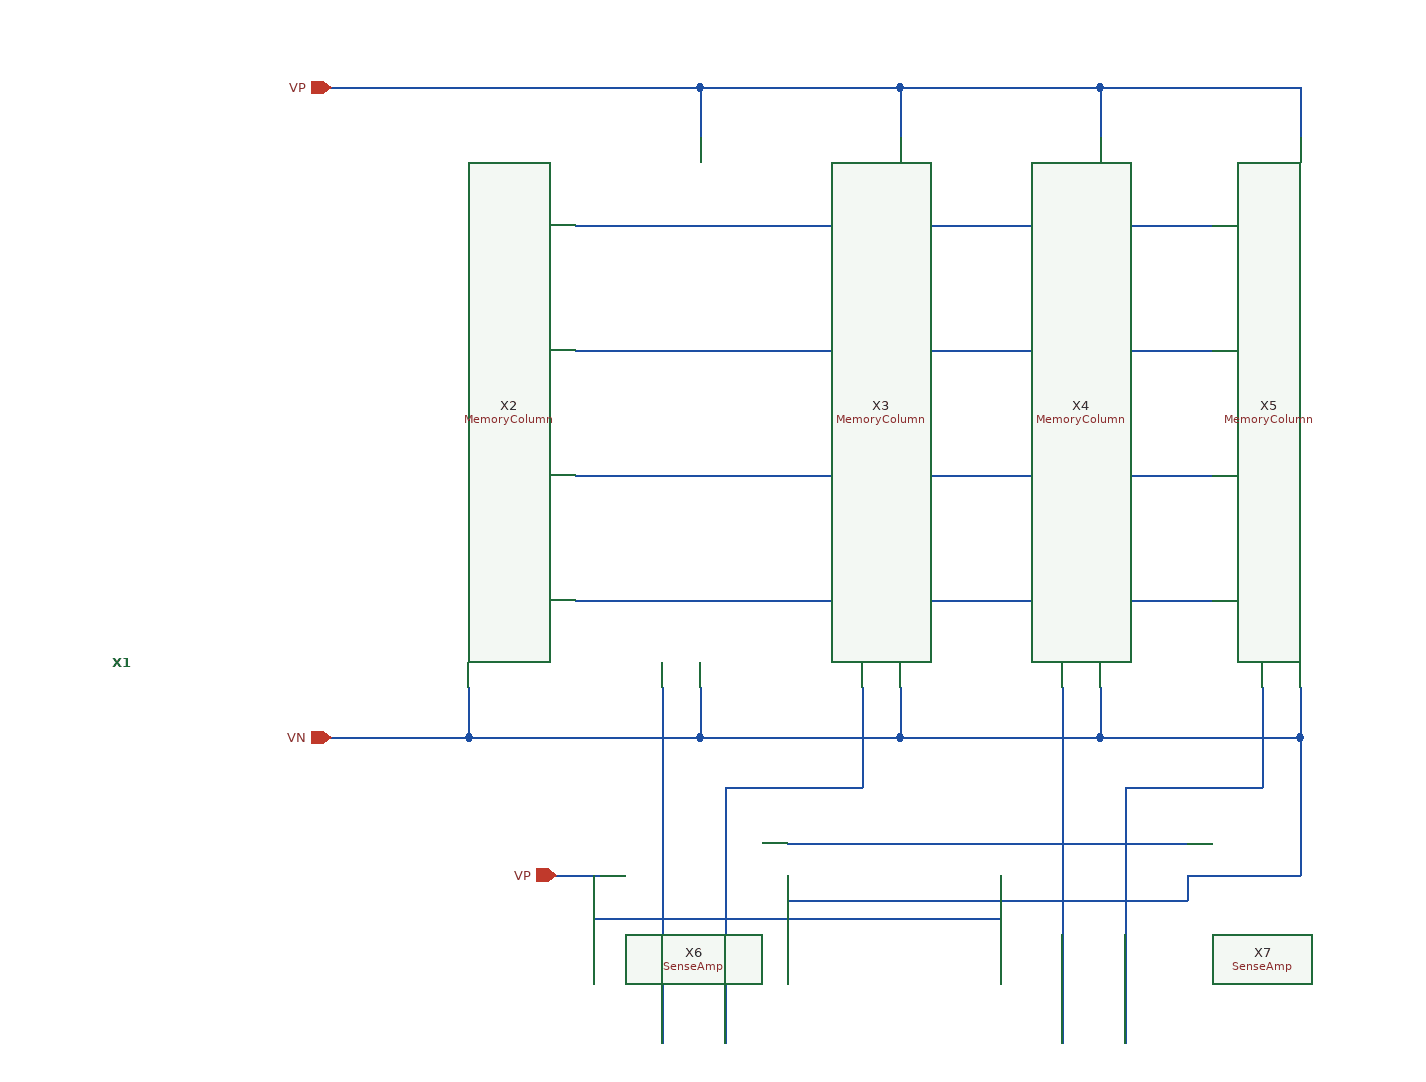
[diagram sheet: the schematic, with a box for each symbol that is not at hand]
v {xschem version=2.9.9 file_version=1.2 }
G {}
K {}
V {}
S {}
E {}
N -40 40 70 40 { lab=VN}
N 70 -0 70 40 { lab=VN}
N 70 40 255 40 { lab=VN}
N 255 -0 255 40 { lab=VN}
N 255 40 415 40 { lab=VN}
N 415 -0 415 40 { lab=VN}
N 415 40 575 40 { lab=VN}
N 575 0 575 40 { lab=VN}
N 575 40 735 40 { lab=VN}
N 735 0 735 40 { lab=VN}
N 735 -480 735 -440 { lab=VP}
N 575 -480 735 -480 { lab=VP}
N 575 -480 575 -440 { lab=VP}
N 415 -480 575 -480 { lab=VP}
N 415 -480 415 -440 { lab=VP}
N 255 -480 255 -440 { lab=VP}
N 255 -480 415 -480 { lab=VP}
N -40 -480 255 -480 { lab=VP}
N 225 -0 225 80 { lab=#net1}
N 385 0 385 80 { lab=#net2}
N 545 0 545 80 { lab=#net3}
N 705 0 705 80 { lab=#net4}
N 155 -70 665 -70 { lab=#net5}
N 155 -170 665 -170 { lab=#net6}
N 155 -270 665 -270 { lab=#net7}
N 155 -370 665 -370 { lab=#net8}
N 275 80 385 80 { lab=#net2}
N 595 80 705 80 { lab=#net4}
N 645 150 730 150 { lab=VN}
N 730 150 735 150 { lab=VN}
N 735 40 735 150 { lab=VN}
N 325 125 645 125 { lab=#net9}
N 140 150 175 150 { lab=VP}
N 645 150 645 170 { lab=VN}
N 325 170 645 170 { lab=VN}
N 325 150 325 170 { lab=VN}
N 495 150 495 185 { lab=VP}
N 170 185 495 185 { lab=VP}
N 170 150 170 185 { lab=VP}
N 225 80 225 285 { lab=#net1}
N 275 80 275 285 { lab=#net2}
N 545 80 545 285 { lab=#net3}
N 595 80 595 285 { lab=#net4}
C {/home/madvlsi/Desktop/MAD_VLSI/FinalProject_DRAM/PreDecode.sym} -215 -20 0 0 {name = X1}
C {/home/madvlsi/Desktop/MAD_VLSI/FinalProject_DRAM/MemoryColumn.sym} 205 -20 0 0 {name=X2}
C {/home/madvlsi/Desktop/MAD_VLSI/FinalProject_DRAM/MemoryColumn.sym} 365 -20 0 0 {name=X3}
C {/home/madvlsi/Desktop/MAD_VLSI/FinalProject_DRAM/MemoryColumn.sym} 525 -20 0 0 {name=X4}
C {/home/madvlsi/Desktop/MAD_VLSI/FinalProject_DRAM/MemoryColumn.sym} 685 -20 0 0 {name=X5}
C {/home/madvlsi/Desktop/MAD_VLSI/FinalProject_DRAM/SenseAmp.sym} 250 100 3 1 {name=X6}
C {/home/madvlsi/Desktop/MAD_VLSI/FinalProject_DRAM/SenseAmp.sym} 570 100 3 1 {name=X7}
C {devices/iopin.sym} 140 150 2 0 {name=p1 lab=VP}
C {devices/iopin.sym} -40 -480 2 0 {name=p2 lab=VP}
C {devices/iopin.sym} -40 40 2 0 {name=p3 lab=VN}
